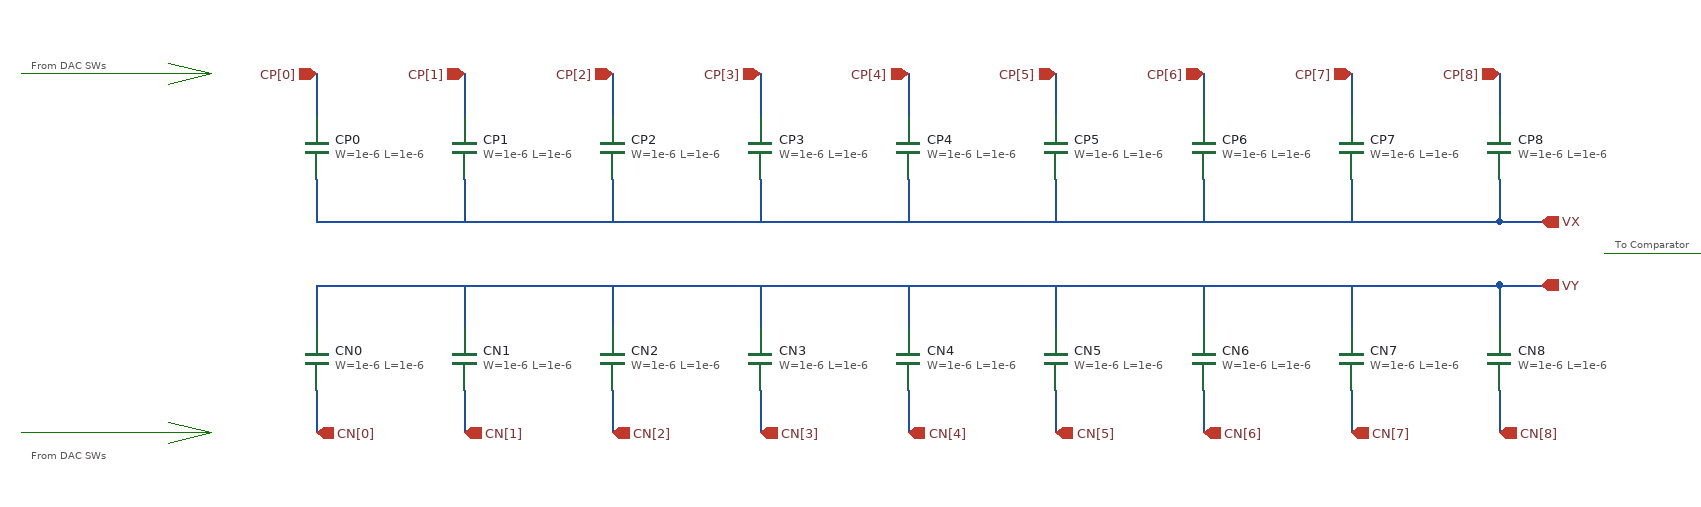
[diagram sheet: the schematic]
v {xschem version=3.4.8RC file_version=1.3}
G {}
K {}
V {}
S {}
F {}
E {}
L 4 160 -400 340 -400 {}
L 4 160 -60 340 -60 {}
L 4 300 -50 340 -60 {}
L 4 300 -70 340 -60 {}
L 4 300 -410 340 -400 {}
L 4 300 -390 340 -400 {}
L 4 1660 -230 1840 -230 {}
L 4 1800 -240 1840 -230 {}
L 4 1800 -220 1840 -230 {}
T {From DAC SWs} 170 -420 0 0 0.3 0.3 {}
T {From DAC SWs} 170 -50 0 0 0.3 0.3 {}
T {To Comparator} 1670 -250 0 0 0.3 0.3 {}
N 1560 -300 1560 -260 {lab=VX}
N 1420 -300 1420 -260 {lab=VX}
N 1280 -300 1280 -260 {lab=VX}
N 1560 -400 1560 -360 {lab=CP[8]}
N 1420 -400 1420 -360 {lab=CP[7]}
N 1280 -400 1280 -360 {lab=CP[6]}
N 440 -260 1560 -260 {lab=VX}
N 440 -300 440 -260 {lab=VX}
N 580 -300 580 -260 {lab=VX}
N 720 -300 720 -260 {lab=VX}
N 860 -300 860 -260 {lab=VX}
N 1000 -300 1000 -260 {lab=VX}
N 1140 -300 1140 -260 {lab=VX}
N 440 -400 440 -360 {lab=CP[0]}
N 580 -400 580 -360 {lab=CP[1]}
N 720 -400 720 -360 {lab=CP[2]}
N 860 -400 860 -360 {lab=CP[3]}
N 1000 -400 1000 -360 {lab=CP[4]}
N 1140 -400 1140 -360 {lab=CP[5]}
N 1560 -200 1560 -160 {lab=VY}
N 1420 -200 1420 -160 {lab=VY}
N 1280 -200 1280 -160 {lab=VY}
N 1560 -100 1560 -60 {lab=CN[8]}
N 1420 -100 1420 -60 {lab=CN[7]}
N 1280 -100 1280 -60 {lab=CN[6]}
N 440 -200 1560 -200 {lab=VY}
N 440 -200 440 -160 {lab=VY}
N 580 -200 580 -160 {lab=VY}
N 720 -200 720 -160 {lab=VY}
N 860 -200 860 -160 {lab=VY}
N 1000 -200 1000 -160 {lab=VY}
N 1140 -200 1140 -160 {lab=VY}
N 440 -100 440 -60 {lab=CN[0]}
N 580 -100 580 -60 {lab=CN[1]}
N 720 -100 720 -60 {lab=CN[2]}
N 860 -100 860 -60 {lab=CN[3]}
N 1000 -100 1000 -60 {lab=CN[4]}
N 1140 -100 1140 -60 {lab=CN[5]}
N 1560 -260 1600 -260 {lab=VX}
N 1560 -200 1600 -200 {lab=VY}
C {symbols/cap_mim_2f0fF.sym} 1560 -330 0 1 {name=CP8
W=1e-6
L=1e-6
model=cap_mim_2f0fF
spiceprefix=X
m=64}
C {symbols/cap_mim_2f0fF.sym} 1420 -330 0 1 {name=CP7
W=1e-6
L=1e-6
model=cap_mim_2f0fF
spiceprefix=X
m=32}
C {symbols/cap_mim_2f0fF.sym} 1280 -330 0 1 {name=CP6
W=1e-6
L=1e-6
model=cap_mim_2f0fF
spiceprefix=X
m=16}
C {symbols/cap_mim_2f0fF.sym} 1140 -330 0 1 {name=CP5
W=1e-6
L=1e-6
model=cap_mim_2f0fF
spiceprefix=X
m=8}
C {symbols/cap_mim_2f0fF.sym} 1000 -330 0 1 {name=CP4
W=1e-6
L=1e-6
model=cap_mim_2f0fF
spiceprefix=X
m=4}
C {symbols/cap_mim_2f0fF.sym} 860 -330 0 1 {name=CP3
W=1e-6
L=1e-6
model=cap_mim_2f0fF
spiceprefix=X
m=2}
C {symbols/cap_mim_2f0fF.sym} 720 -330 0 1 {name=CP2
W=1e-6
L=1e-6
model=cap_mim_2f0fF
spiceprefix=X
m=1}
C {symbols/cap_mim_2f0fF.sym} 580 -330 0 1 {name=CP1
W=1e-6
L=1e-6
model=cap_mim_2f0fF
spiceprefix=X
m=1}
C {symbols/cap_mim_2f0fF.sym} 440 -330 0 1 {name=CP0
W=1e-6
L=1e-6
model=cap_mim_2f0fF
spiceprefix=X
m=1}
C {symbols/cap_mim_2f0fF.sym} 1560 -130 2 0 {name=CN8
W=1e-6
L=1e-6
model=cap_mim_2f0fF
spiceprefix=X
m=64}
C {symbols/cap_mim_2f0fF.sym} 1420 -130 2 0 {name=CN7
W=1e-6
L=1e-6
model=cap_mim_2f0fF
spiceprefix=X
m=32}
C {symbols/cap_mim_2f0fF.sym} 1280 -130 2 0 {name=CN6
W=1e-6
L=1e-6
model=cap_mim_2f0fF
spiceprefix=X
m=16}
C {symbols/cap_mim_2f0fF.sym} 1140 -130 2 0 {name=CN5
W=1e-6
L=1e-6
model=cap_mim_2f0fF
spiceprefix=X
m=8}
C {symbols/cap_mim_2f0fF.sym} 1000 -130 2 0 {name=CN4
W=1e-6
L=1e-6
model=cap_mim_2f0fF
spiceprefix=X
m=4}
C {symbols/cap_mim_2f0fF.sym} 860 -130 2 0 {name=CN3
W=1e-6
L=1e-6
model=cap_mim_2f0fF
spiceprefix=X
m=2}
C {symbols/cap_mim_2f0fF.sym} 720 -130 2 0 {name=CN2
W=1e-6
L=1e-6
model=cap_mim_2f0fF
spiceprefix=X
m=1}
C {symbols/cap_mim_2f0fF.sym} 580 -130 2 0 {name=CN1
W=1e-6
L=1e-6
model=cap_mim_2f0fF
spiceprefix=X
m=1}
C {symbols/cap_mim_2f0fF.sym} 440 -130 2 0 {name=CN0
W=1e-6
L=1e-6
model=cap_mim_2f0fF
spiceprefix=X
m=1}
C {iopin.sym} 1600 -260 2 1 {name=p19 lab=VX}
C {iopin.sym} 1600 -200 2 1 {name=p18 lab=VY}
C {ipin.sym} 440 -400 1 0 {name=p20 lab=CP[0]}
C {ipin.sym} 580 -400 1 0 {name=p1 lab=CP[1]}
C {ipin.sym} 720 -400 1 0 {name=p2 lab=CP[2]}
C {ipin.sym} 860 -400 1 0 {name=p3 lab=CP[3]}
C {ipin.sym} 1000 -400 1 0 {name=p4 lab=CP[4]}
C {ipin.sym} 1140 -400 1 0 {name=p5 lab=CP[5]}
C {ipin.sym} 1280 -400 1 0 {name=p6 lab=CP[6]}
C {ipin.sym} 1420 -400 1 0 {name=p7 lab=CP[7]}
C {ipin.sym} 1560 -400 1 0 {name=p8 lab=CP[8]}
C {ipin.sym} 440 -60 1 1 {name=p9 lab=CN[0]}
C {ipin.sym} 580 -60 1 1 {name=p10 lab=CN[1]}
C {ipin.sym} 720 -60 1 1 {name=p11 lab=CN[2]}
C {ipin.sym} 860 -60 1 1 {name=p12 lab=CN[3]}
C {ipin.sym} 1000 -60 1 1 {name=p13 lab=CN[4]}
C {ipin.sym} 1140 -60 1 1 {name=p14 lab=CN[5]}
C {ipin.sym} 1280 -60 1 1 {name=p15 lab=CN[6]}
C {ipin.sym} 1420 -60 1 1 {name=p16 lab=CN[7]}
C {ipin.sym} 1560 -60 1 1 {name=p17 lab=CN[8]}
